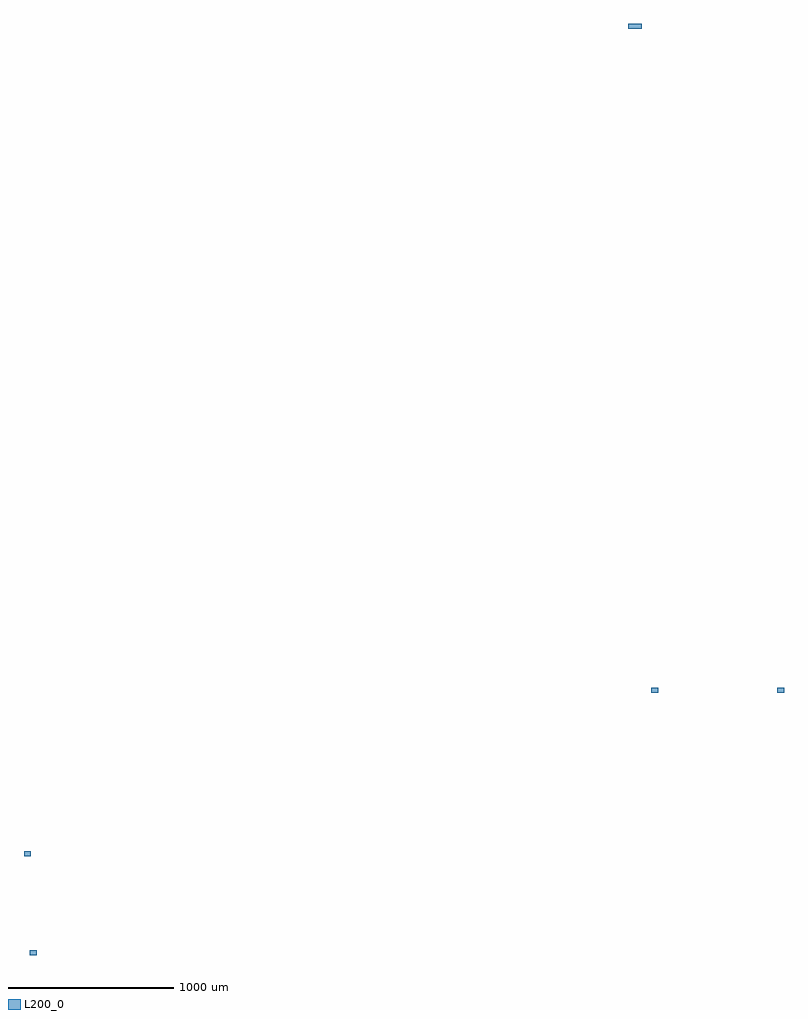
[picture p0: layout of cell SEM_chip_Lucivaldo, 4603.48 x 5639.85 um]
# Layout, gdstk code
import gdstk
lib = gdstk.Library(unit=1e-6, precision=1e-09)
def R(c, l, rs):  # rectangles x0, y0, x1, y1
    for r in rs: c.add(gdstk.rectangle(r[:2], r[2:], *l))
L200_0 = (200, 0)

sem_i0_dc1_40_2672_37__1 = lib.new_cell('sem_I0-DC1_40_2672.37_-1935.09')
R(sem_i0_dc1_40_2672_37__1, L200_0, [(2652.373,-1950.09,2692.373,-1920.09)])

sem_i0_dc2_40_3434_95__1 = lib.new_cell('sem_I0-DC2_40_3434.95_-1935.71')
R(sem_i0_dc2_40_3434_95__1, L200_0, [(3414.955,-1950.711,3454.955,-1920.711)])

sem_lm_mzi1_40__1128_53_ = lib.new_cell('sem_LM-MZI1_40_-1128.53_-2925.4')
R(sem_lm_mzi1_40__1128_53_, L200_0, [(-1148.53,-2940.4,-1108.53,-2910.4)])

sem_ml_mzi1_40__1092_29_ = lib.new_cell('sem_ML-MZI1_40_-1092.29_-3523.85')
R(sem_ml_mzi1_40__1092_29_, L200_0, [(-1112.29,-3538.85,-1072.29,-3508.85)])

sem_it_swg1_40_2573_2086 = lib.new_cell('sem_IT-SWG1_40_2573_2086')
R(sem_it_swg1_40_2573_2086, L200_0, [(2553,2071,2593,2101)])

sem_it_swg2_40_2532_2086 = lib.new_cell('sem_IT-SWG2_40_2532_2086')
R(sem_it_swg2_40_2532_2086, L200_0, [(2512,2071,2552,2101)])

sem_chip_lucivaldo = lib.new_cell('SEM_chip_Lucivaldo')
sem_chip_lucivaldo.add(gdstk.Reference(sem_i0_dc1_40_2672_37__1, (0,0)))
sem_chip_lucivaldo.add(gdstk.Reference(sem_i0_dc2_40_3434_95__1, (0,0)))
sem_chip_lucivaldo.add(gdstk.Reference(sem_lm_mzi1_40__1128_53_, (0,0)))
sem_chip_lucivaldo.add(gdstk.Reference(sem_ml_mzi1_40__1092_29_, (0,0)))
sem_chip_lucivaldo.add(gdstk.Reference(sem_it_swg1_40_2573_2086, (0,0)))
sem_chip_lucivaldo.add(gdstk.Reference(sem_it_swg2_40_2532_2086, (0,0)))

lib.write_gds('SEM_chip_Lucivaldo.gds')
